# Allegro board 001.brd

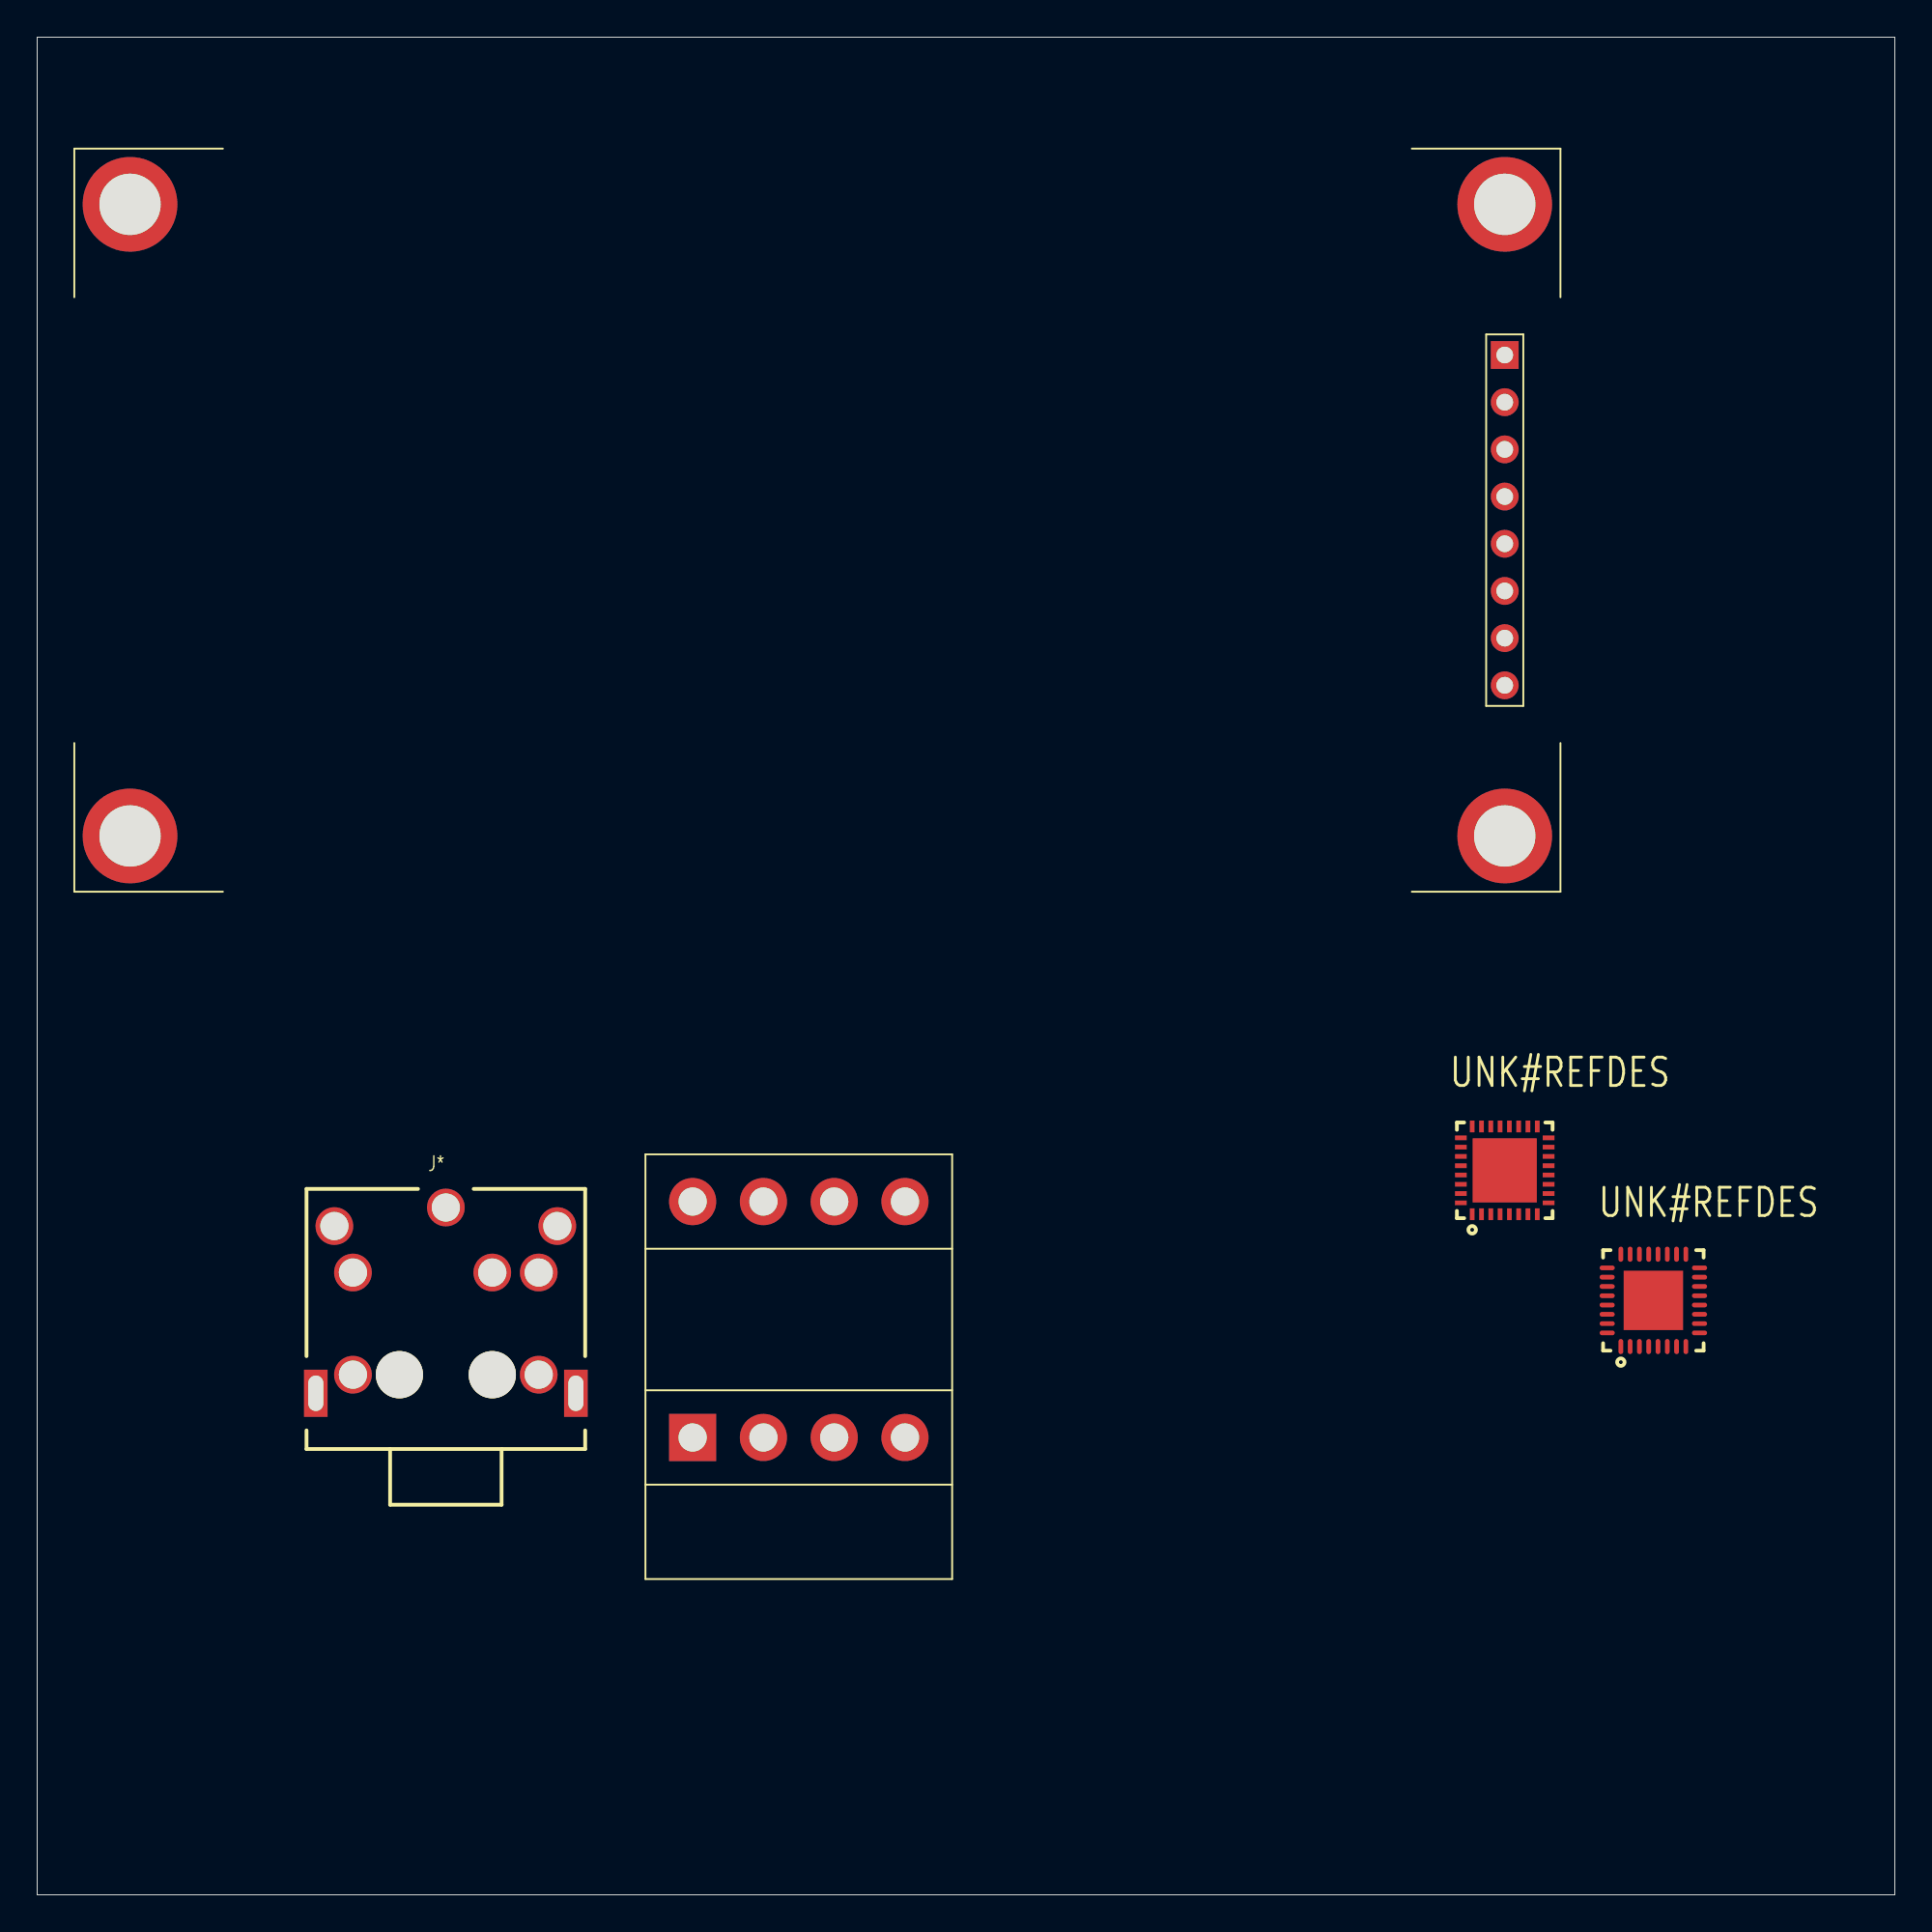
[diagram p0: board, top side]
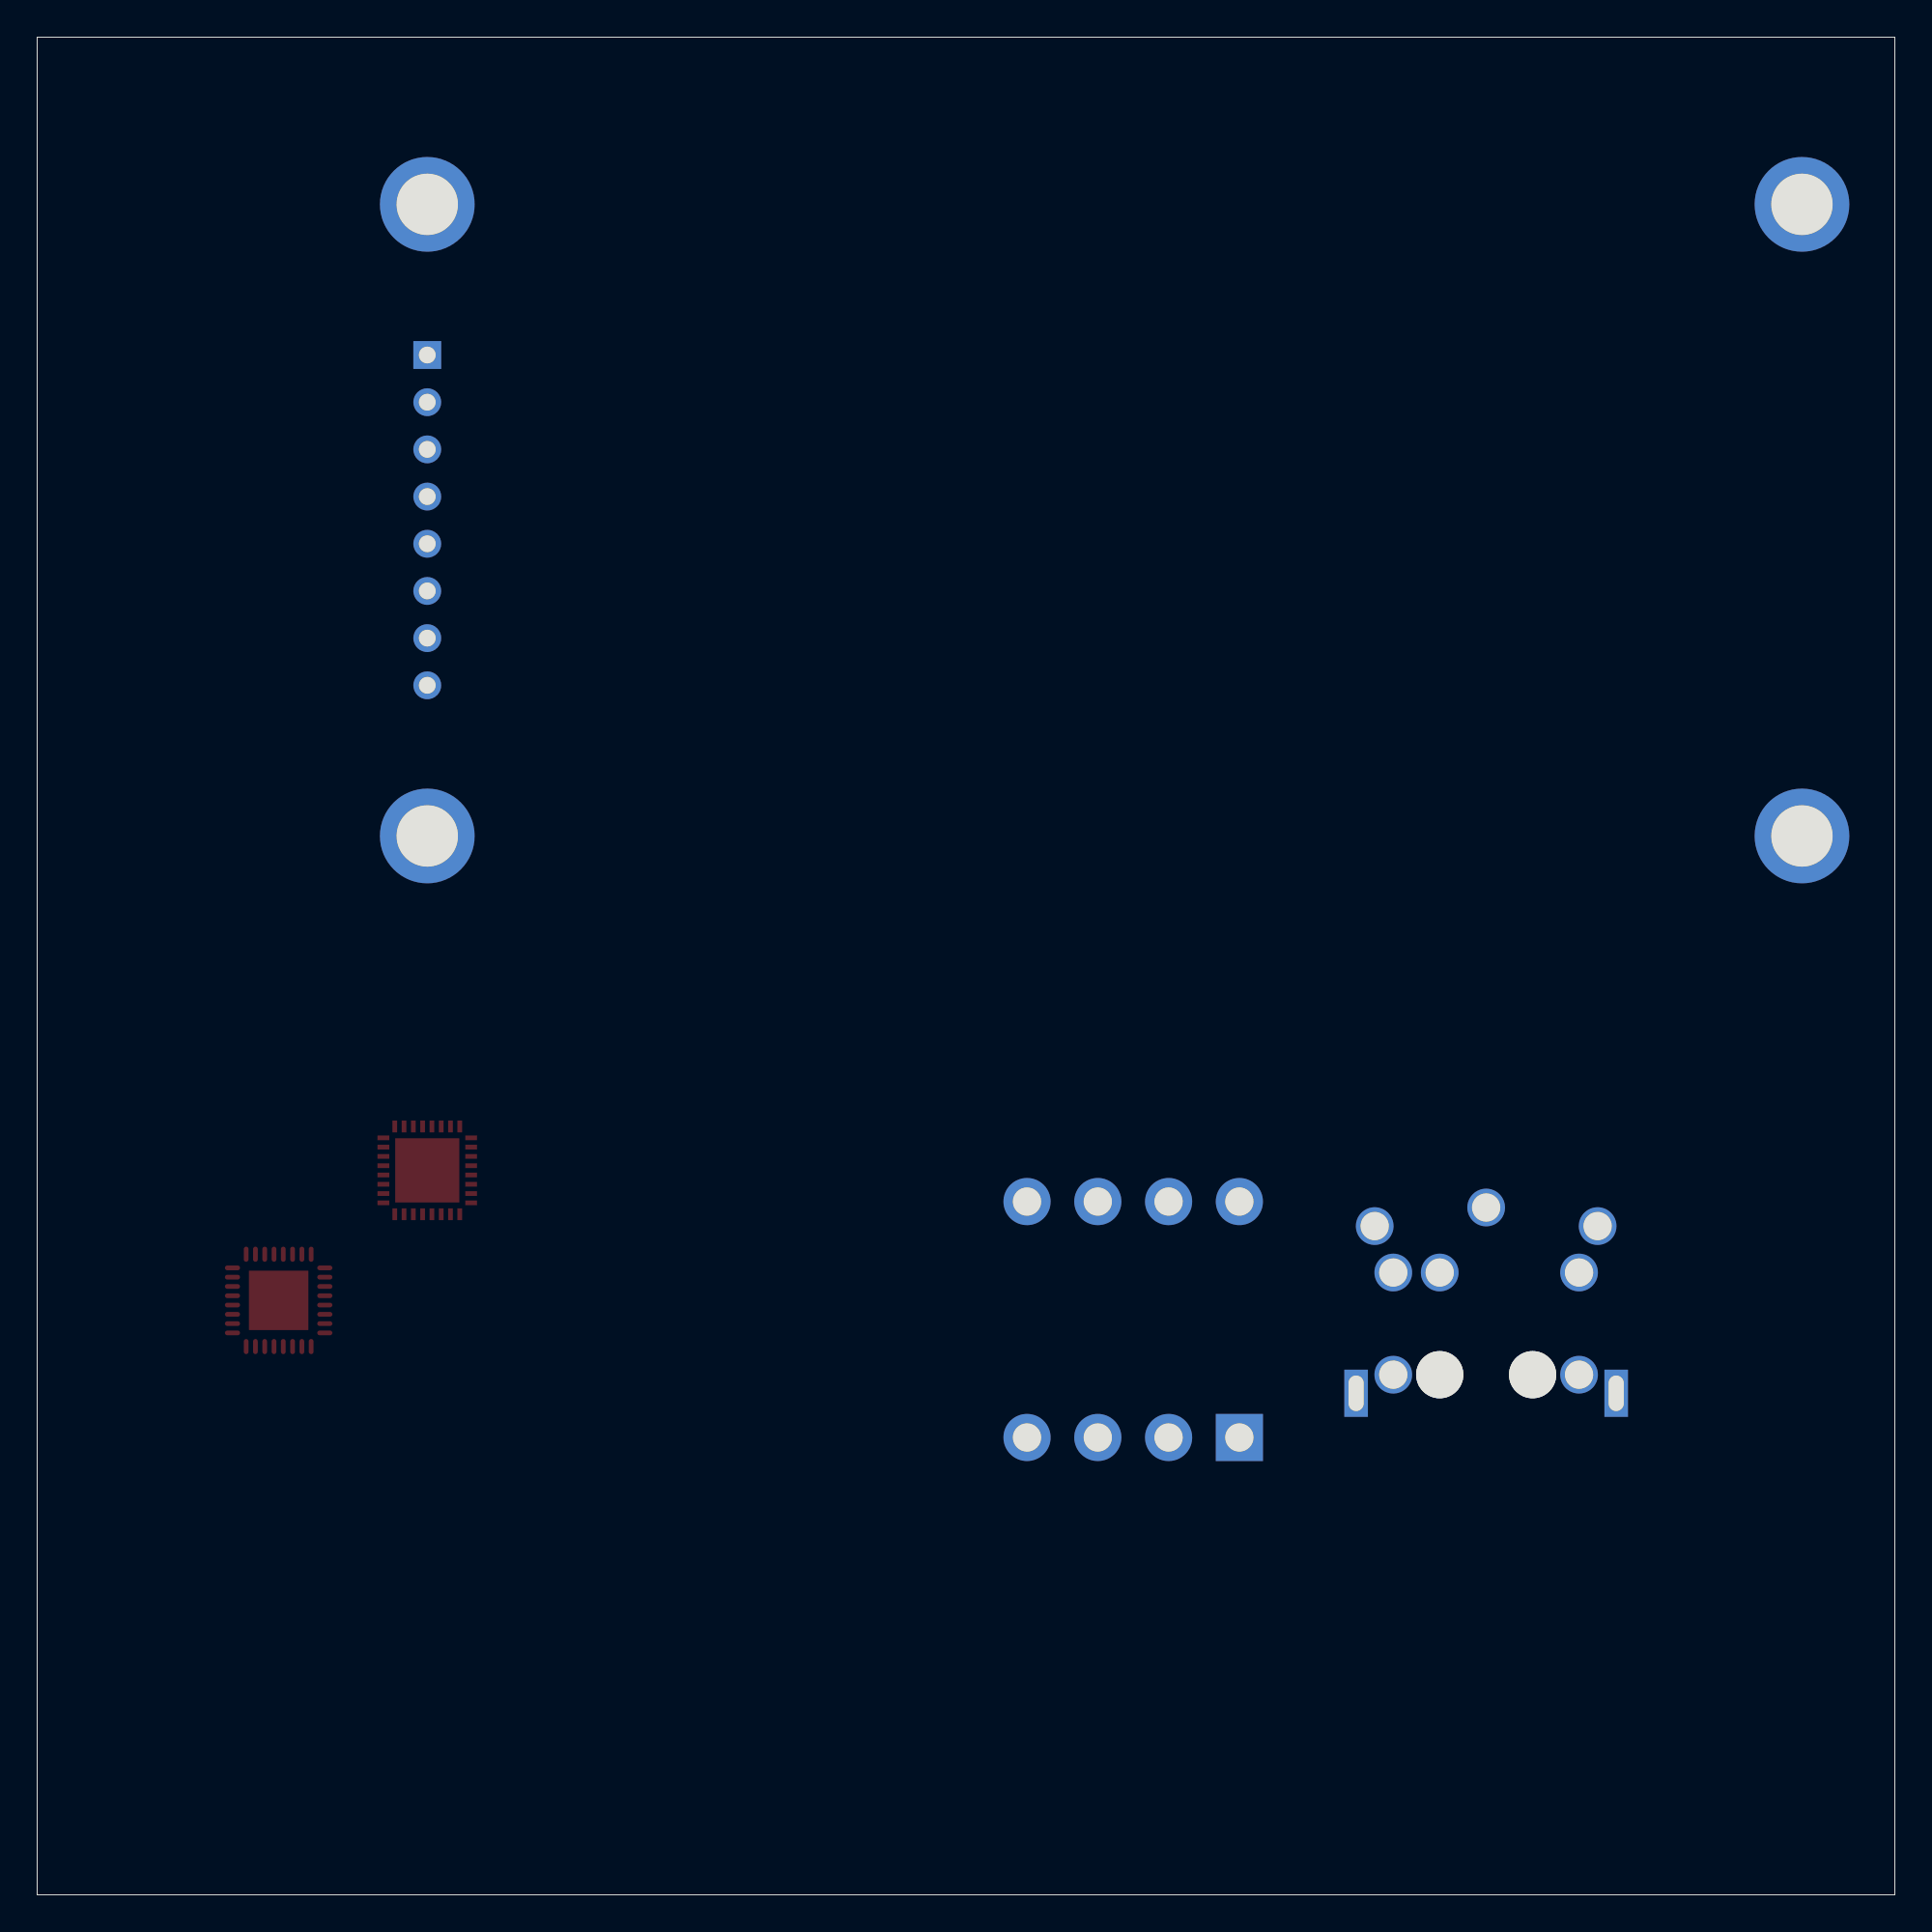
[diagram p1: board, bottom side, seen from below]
Outline 100 x 100 mm; copper layers: TOP, LAYER2, LAYER3, LAYER4, LAYER5, BOTTOM. Coordinates in mm from the lower left corner of the outline.
Outline path: 0,100 100,100 100,0 0,0 0,100

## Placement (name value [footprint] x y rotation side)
J*  -  [unnamed]  2 54 0 top
J*#2  -  [unnamed#4]  22 27 0 top
J*#3  -  [unnamed#5]  41 17 0 top
UNK#REFDES  -  [unnamed#2]  87 32 0 top
UNK#REFDES#2  -  [unnamed#3]  79 39 0 top

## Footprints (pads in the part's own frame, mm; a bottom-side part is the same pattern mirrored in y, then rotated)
unnamed
  round 5.1 hole 3.3: (3,37) (3,3) (77,37) (77,3)
  rect 1.5x1.5 hole 0.9: 1(77,28.89)
  round 1.5 hole 0.9: 2(77,26.35) 3(77,23.81) 4(77,21.27) 5(77,18.73) 6(77,16.19) 7(77,13.65) 8(77,11.11)
unnamed#2
  oval 0.254x0.813 smd: 1(-1.75,-2.485) 2(-1.25,-2.485) 3(-0.75,-2.485) 4(-0.25,-2.485) 5(0.25,-2.485) 6(0.75,-2.485) 7(1.25,-2.485) 8(1.75,-2.485) 17(1.75,2.485) 18(1.25,2.485) 19(0.75,2.485) 20(0.25,2.485) 21(-0.25,2.485) 22(-0.75,2.485) 23(-1.25,2.485) 24(-1.75,2.485)
  oval 0.813x0.254 smd: 9(2.485,-1.75) 10(2.485,-1.25) 11(2.485,-0.75) 12(2.485,-0.25) 13(2.485,0.25) 14(2.485,0.75) 15(2.485,1.25) 16(2.485,1.75) 25(-2.485,1.75) 26(-2.485,1.25) 27(-2.485,0.75) 28(-2.485,0.25) 29(-2.485,-0.25) 30(-2.485,-0.75) 31(-2.485,-1.25) 32(-2.485,-1.75)
  rect 3.2x3.2 smd: 33(0,0)
unnamed#3
  rect 0.254x0.635 smd: 1(-1.75,-2.362) 2(-1.25,-2.362) 3(-0.75,-2.362) 4(-0.25,-2.362) 5(0.25,-2.362) 6(0.75,-2.362) 7(1.25,-2.362) 8(1.75,-2.362) 17(1.75,2.362) 18(1.25,2.362) 19(0.75,2.362) 20(0.25,2.362) 21(-0.25,2.362) 22(-0.75,2.362) 23(-1.25,2.362) 24(-1.75,2.362)
  rect 0.635x0.254 smd: 9(2.362,-1.75) 10(2.362,-1.25) 11(2.362,-0.75) 12(2.362,-0.25) 13(2.362,0.25) 14(2.362,0.75) 15(2.362,1.25) 16(2.362,1.75) 25(-2.362,1.75) 26(-2.362,1.25) 27(-2.362,0.75) 28(-2.362,0.25) 29(-2.362,-0.25) 30(-2.362,-0.75) 31(-2.362,-1.25) 32(-2.362,-1.75)
  rect 3.454x3.454 smd: 33(0,0)
unnamed#4
  round 2.54 hole 2.54 unplated: (-2.5,1) (2.5,1)
  round 2.03 hole 1.52: 1(-6,9) 2(0,10) 3(6,9) 4(5,1) 6(5,6.5) 7(2.5,6.5) 8(-5,6.5) 9(-5,1)
  rect 1.27x2.54 hole 0.81x1.91: 5(7,0) 10(-7,0)
unnamed#5
  rect 2.54x2.54 hole 1.52: 1(-5.715,7.62)
  round 2.54 hole 1.52: 2(-1.905,7.62) 3(1.905,7.62) 4(5.715,7.62) 5(-5.715,20.32) 6(-1.905,20.32) 7(1.905,20.32) 8(5.715,20.32)

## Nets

Pads without a net: J* 1 2 3 4 5 6 7 8; J*#2 1 2 3 4 5 6 7 8 9 10; J*#3 1 2 3 4 5 6 7 8; UNK#REFDES 1 2 3 4 5 6 7 8 9 10 11 12 13 14 15 16 17 18 19 20 21 22 23 24 25 26 27 28 29 30 31 32 33; UNK#REFDES#2 1 2 3 4 5 6 7 8 9 10 11 12 13 14 15 16 17 18 19 20 21 22 23 24 25 26 27 28 29 30 31 32 33
